One B-rep face of a CAD part: STEP entity #456.
In plain terms, the planar face has unit normal (1, 0, 0).
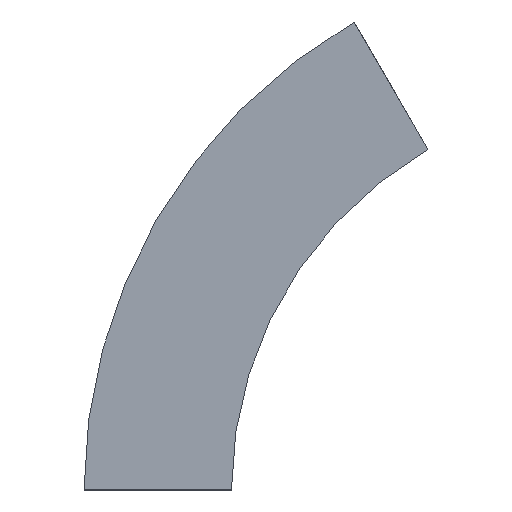
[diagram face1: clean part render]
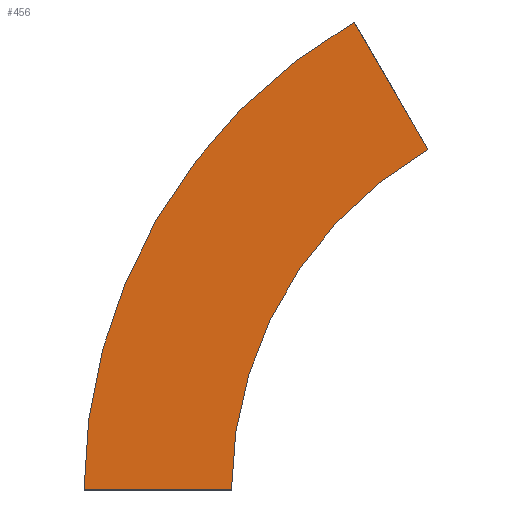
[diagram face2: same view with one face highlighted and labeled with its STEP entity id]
Its self-contained STEP definition (entity closure, numbers rounded to 3 decimals):
#8 = LINE ( 'NONE', #92, #127 ) ;
#11 = EDGE_CURVE ( 'NONE', #338, #379, #459, .T. ) ;
#33 = CARTESIAN_POINT ( 'NONE',  ( 0., 0., 0. ) ) ;
#47 = CARTESIAN_POINT ( 'NONE',  ( 0., -300., 0. ) ) ;
#68 = DIRECTION ( 'NONE',  ( 0., 0., -1. ) ) ;
#78 = CARTESIAN_POINT ( 'NONE',  ( 0., -150., 259.808 ) ) ;
#92 = CARTESIAN_POINT ( 'NONE',  ( 0., 0., 0. ) ) ;
#97 = DIRECTION ( 'NONE',  ( 1., 0., 0. ) ) ;
#127 = VECTOR ( 'NONE', #271, 1000. ) ;
#147 = DIRECTION ( 'NONE',  ( 0., 1., 0. ) ) ;
#160 = CARTESIAN_POINT ( 'NONE',  ( 0., 0., 0. ) ) ;
#169 = CARTESIAN_POINT ( 'NONE',  ( 0., 112.5, 0. ) ) ;
#187 = EDGE_CURVE ( 'NONE', #329, #379, #436, .T. ) ;
#194 = CARTESIAN_POINT ( 'NONE',  ( 0., -150., 259.808 ) ) ;
#195 = CARTESIAN_POINT ( 'NONE',  ( 0., -300., 0. ) ) ;
#208 = AXIS2_PLACEMENT_3D ( 'NONE', #33, #342, #68 ) ;
#209 = VECTOR ( 'NONE', #541, 1000. ) ;
#223 = EDGE_CURVE ( 'NONE', #277, #338, #275, .T. ) ;
#239 = AXIS2_PLACEMENT_3D ( 'NONE', #47, #368, #147 ) ;
#263 = CARTESIAN_POINT ( 'NONE',  ( 0., -93.75, 357.235 ) ) ;
#271 = DIRECTION ( 'NONE',  ( 0., 1., 0. ) ) ;
#275 = CIRCLE ( 'NONE', #343, 300. ) ;
#277 = VERTEX_POINT ( 'NONE', #160 ) ;
#284 = ORIENTED_EDGE ( 'NONE', *, *, #223, .F. ) ;
#328 = DIRECTION ( 'NONE',  ( 0., 1., 0. ) ) ;
#329 = VERTEX_POINT ( 'NONE', #169 ) ;
#338 = VERTEX_POINT ( 'NONE', #78 ) ;
#342 = DIRECTION ( 'NONE',  ( 1., 0., 0. ) ) ;
#343 = AXIS2_PLACEMENT_3D ( 'NONE', #195, #97, #328 ) ;
#368 = DIRECTION ( 'NONE',  ( 1., 0., 0. ) ) ;
#379 = VERTEX_POINT ( 'NONE', #263 ) ;
#412 = ORIENTED_EDGE ( 'NONE', *, *, #527, .T. ) ;
#413 = EDGE_LOOP ( 'NONE', ( #525, #550, #284, #412 ) ) ;
#435 = FACE_OUTER_BOUND ( 'NONE', #413, .T. ) ;
#436 = CIRCLE ( 'NONE', #239, 412.5 ) ;
#456 = ADVANCED_FACE ( 'NONE', ( #435 ), #560, .T. ) ;
#459 = LINE ( 'NONE', #194, #209 ) ;
#525 = ORIENTED_EDGE ( 'NONE', *, *, #187, .T. ) ;
#527 = EDGE_CURVE ( 'NONE', #277, #329, #8, .T. ) ;
#541 = DIRECTION ( 'NONE',  ( 0., 0.5, 0.866 ) ) ;
#550 = ORIENTED_EDGE ( 'NONE', *, *, #11, .F. ) ;
#560 = PLANE ( 'NONE',  #208 ) ;
